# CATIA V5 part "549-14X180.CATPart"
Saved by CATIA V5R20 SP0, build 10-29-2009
Part number: 549-14X180
Definition: NONE
Nomenclature: 549-14X180
Source: Unknown
Description: 549-14X180
Bounding box of the stored display mesh (mm): x 0 to 180, y -8.5 to 8.5, z -8.5 to 8.5
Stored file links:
  C:\Users\Utente\Desktop\IO LAVORO\3D X SITO CF\X SITO\PLASTICA\549\549-14X180.CATPart

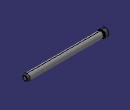
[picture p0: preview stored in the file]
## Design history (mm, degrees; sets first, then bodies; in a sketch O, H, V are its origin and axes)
Body1 "549-14X180" (main body)
  Solid1: solid without history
